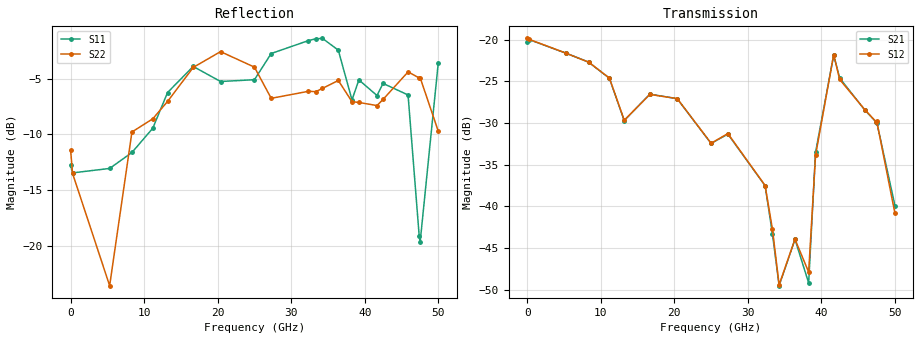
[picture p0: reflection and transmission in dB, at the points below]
!Keysight Technologies,N5245B,MY58422270,A.16.20.02
!Date: Thursday, March 05, 2026 01:23:14
!Correction: S11(C  2-Port  )
!S21(C  2-Port  )
!S12(C  2-Port  )
!S22(C  2-Port  )
!S2P File: Measurements: S11, S21, S12, S22:
# Hz S  dB  R 50
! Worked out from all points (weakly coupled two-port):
!   3201 points, 10 MHz to 50 GHz, reference 50 ohm
!   highest |S21| = -20.00 dB at 275.6 MHz (marker M1); lowest = -49.5 dB at 34.25 GHz (marker M2)
!   lowest |S11| = -19.7 dB at 47.53 GHz (marker M3), VSWR 1.23, Z = 46 + j9.16 ohm
!   |S11| at or under -10 dB: start of sweep to 10.15 GHz; 11.35 GHz to 11.92 GHz (568.8 MHz wide, 4.89 % of centre); 46.67 GHz to 48.28 GHz (1.609 GHz wide, 3.39 % of centre)
!   |S22| runs from -23.6 to -2.5 dB; largest |S21 - S12| = 0.005
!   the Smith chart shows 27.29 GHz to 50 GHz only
!   S11 on the Smith chart (normalised r, x): 27.29 GHz: 0.18, +0.38; 32.35 GHz: 0.43, +1.89; 36.41 GHz: 2.28, -3.23; 42.49 GHz: 0.98, -1.26; 47.41 GHz: 0.84, +0.13; 50 GHz: 0.62, -1.34
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1e7  -12.78 -3.3  -20.29 5.0  -19.85 5.3  -11.38 30.1
2.755719e8  -13.45 -11.9  -20.00 -11.1  -19.97 -11.0  -13.49 -12.2
5.321438e9  -13.05 -130.7  -21.64 151.4  -21.64 151.3  -23.57 -134.9
8.352081e9  -11.62 174.4  -22.70 24.4  -22.70 24.5  -9.78 -154.9
1.117964e10  -9.45 105.8  -24.63 -85.0  -24.61 -85.0  -8.60 90.9
1.319486e10  -6.24 63.2  -29.71 -142.6  -29.66 -142.8  -7.04 -19.7
1.667854e10  -3.90 -43.8  -26.54 157.1  -26.57 157.5  -3.99 -139.5
2.039655e10  -5.25 -121.5  -27.08 40.3  -27.07 40.1  -2.57 155.6
2.5005e10  -5.09 179.6  -32.44 -63.9  -32.43 -64.2  -3.96 71.4
2.728579e10  -2.74 137.5  -31.33 -115.7  -31.26 -116.3  -6.76 30.4
3.234728e10  -1.58 53.9  -37.51 45.6  -37.49 45.9  -6.13 -104.3
3.334708e10  -1.42 36.1  -43.29 5.2  -42.74 5.3  -6.16 -126.1
3.425315e10  -1.38 20.0  -49.50 -84.5  -49.40 -60.5  -5.87 -144.9
3.640897e10  -2.44 -23.8  -43.94 112.1  -43.93 121.4  -5.16 173.7
3.826797e10  -6.90 -22.2  -49.17 -40.8  -47.87 -90.7  -7.06 139.3
3.920528e10  -5.11 -32.6  -33.51 92.0  -33.87 92.1  -7.13 137.6
4.167354e10  -6.51 -52.6  -21.85 -59.1  -21.80 -59.2  -7.41 117.6
4.248588e10  -5.42 -58.6  -24.61 -120.8  -24.78 -121.1  -6.86 113.1
4.589145e10  -6.46 -117.3  -28.43 55.3  -28.39 54.5  -4.39 63.2
4.740677e10  -19.11 136.6  -29.85 -0.6  -29.82 -0.9  -4.93 42.7
4.753174e10  -19.68 108.3  -29.94 -3.5  -29.81 -3.4  -4.90 41.3
5e10  -3.56 -66.4  -39.89 -126.7  -40.83 -141.1  -9.71 2.4
